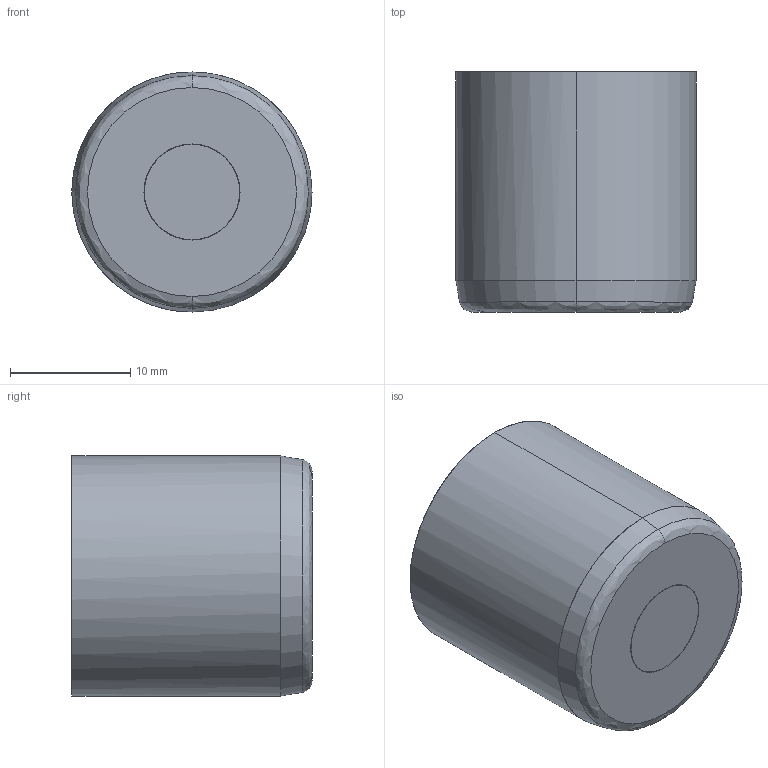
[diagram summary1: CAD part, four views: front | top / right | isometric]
IGES file: header records copied from the file, then geometry measured from it (millimetres).
Start section: START RECORD GO HERE.
Global section: file name: fa2007sf.igs; native system: DASSAULT SYSTEMES CATIA V5 R20 - www.3ds.com; preprocessor: CATIA Version 5 Release 20 ; author: Utente; organization: NB04-ASUS; date: 20201108.084101; units: millimetre
Bounding box: 20 x 20 x 20 mm (x, y, z)
Surface area: 3296.9 mm2 (no closed solid volume)
Topology: 0 solids, 0 shells, 400 faces, 1998 edges, 1992 vertices
Faces by surface type: revolution 197, plane 133, bspline 70
